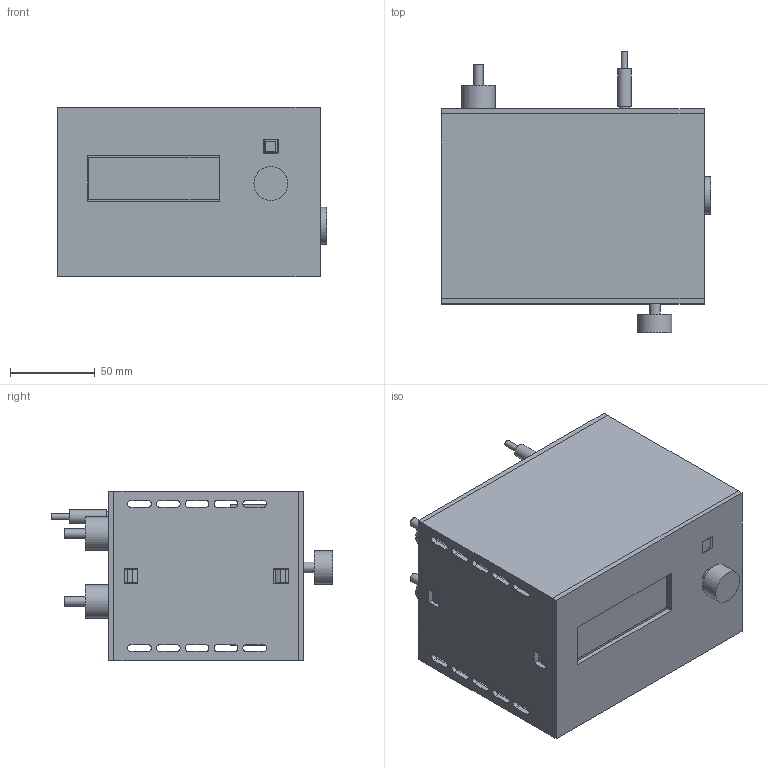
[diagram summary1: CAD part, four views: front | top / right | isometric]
STEP (ISO 10303-21) file: header records copied from the file, then geometry measured from it (millimetres).
FILE_DESCRIPTION(('Open CASCADE Model'),'2;1');
FILE_NAME('Open CASCADE Shape Model','2026-11-09T10:21:47',('Author'),( 'Open CASCADE'),'Open CASCADE STEP processor 7.8','Open CASCADE 7.8' ,'Unknown');
FILE_SCHEMA(('AUTOMOTIVE_DESIGN { 1 0 10303 214 1 1 1 1 }'));
Length unit declared in the file: millimetre
Products named in the file (113): Laboratory_controller_fit_study_v10; 01_Pieces_imprimees; 01_Shell_open_front_and_rear; 02_Removable_front_LCD_A; 03_B_removable_carrier; 04_Rear_panel_with_latches; 05_Translucent_optical_insert; 06_BH1750_removable_carrier; 02_Carte_A_reference; PCB_A; A_C1_ENVELOPE; A_C2_ENVELOPE; A_C3_ENVELOPE; A_D1_ENVELOPE; A_D2_ENVELOPE; A_J1_ENVELOPE; A_J2_ENVELOPE; A_J3_ENVELOPE; A_J4_ENVELOPE; A_J5_ENVELOPE; A_J6_ENVELOPE; A_J7_ENVELOPE; A_JP1_ENVELOPE; A_R1_ENVELOPE; A_R2_ENVELOPE; A_R3_ENVELOPE; A_R4_ENVELOPE; A_R5_ENVELOPE; A_R6_ENVELOPE; A_R7_ENVELOPE; A_U2_ENVELOPE; A_DEVKIT_SOCKET_1; A_DEVKIT_MALE_HEADER_SPACER_1; A_DEVKIT_SOCKET_2; A_DEVKIT_MALE_HEADER_SPACER_2; A_DEVKIT_PCB_REFERENCE_54x27; A_DEVKIT_RF_SHIELD_ENVELOPE; A_DEVKIT_USB_BRIDGE_ENVELOPE; A_DEVKIT_USB_C_ENVELOPE; 03_Carte_B_reference ...
Assembly tree (112 placements, depth 3):
  Laboratory_controller_fit_study_v10
    01_Pieces_imprimees
      01_Shell_open_front_and_rear
      02_Removable_front_LCD_A
      03_B_removable_carrier
      04_Rear_panel_with_latches
      05_Translucent_optical_insert
      06_BH1750_removable_carrier
    02_Carte_A_reference
      PCB_A
      A_C1_ENVELOPE
      A_C2_ENVELOPE
      A_C3_ENVELOPE
      A_D1_ENVELOPE
      A_D2_ENVELOPE
      A_J1_ENVELOPE
      A_J2_ENVELOPE
      A_J3_ENVELOPE
      A_J4_ENVELOPE
      A_J5_ENVELOPE
      A_J6_ENVELOPE
      A_J7_ENVELOPE
      A_JP1_ENVELOPE
      A_R1_ENVELOPE
      A_R2_ENVELOPE
      A_R3_ENVELOPE
      A_R4_ENVELOPE
      A_R5_ENVELOPE
      A_R6_ENVELOPE
      A_R7_ENVELOPE
      A_U2_ENVELOPE
      A_DEVKIT_SOCKET_1
      A_DEVKIT_MALE_HEADER_SPACER_1
      A_DEVKIT_SOCKET_2
      A_DEVKIT_MALE_HEADER_SPACER_2
      A_DEVKIT_PCB_REFERENCE_54x27
      A_DEVKIT_RF_SHIELD_ENVELOPE
      A_DEVKIT_USB_BRIDGE_ENVELOPE
      A_DEVKIT_USB_C_ENVELOPE
    03_Carte_B_reference
      PCB_B
      B_C1_ENVELOPE
      B_C10_ENVELOPE
      B_C2_ENVELOPE
      B_C3_ENVELOPE
      B_C4_ENVELOPE
      B_C5_ENVELOPE
      B_C6_ENVELOPE
      B_C7_ENVELOPE
      B_C8_ENVELOPE
      B_C9_ENVELOPE
      B_D2_ENVELOPE
      B_D3_ENVELOPE
      B_D4_ENVELOPE
      B_D5_ENVELOPE
      B_D6_ENVELOPE
      B_D7_ENVELOPE
      B_D8_ENVELOPE
      B_D9_ENVELOPE
      B_F1_ENVELOPE
Bounding box: 159 x 166 x 100 mm (x, y, z)
Volume: 418084.1 mm3; surface area: 319560.4 mm2
Topology: 105 solids, 106 shells, 1212 faces, 2852 edges, 1889 vertices
Faces by surface type: plane 1124, cylinder 88
Full cylindrical faces by diameter (mm): 2.2 x12, 3 x3, 3.5 x2, 5.5 x2, 5.6 x1, 6 x2, 6.3 x3, 6.4 x1, 7.2 x1, 8 x2, 8.2 x1, 9 x1, 12 x4, 12.5 x2, 14 x1, 15 x2, 16 x1, 20 x5, 22 x2
Entity records: 73220 total; most frequent: CARTESIAN_POINT 13174, DIRECTION 10270, LINE 7037, VECTOR 7037, ORIENTED_EDGE 5704, PCURVE 5704, DEFINITIONAL_REPRESENTATION 5704, EDGE_CURVE 2852
One B-rep face of a CAD part: STEP entity #1736.
In plain terms, the planar face has unit normal (0, 0, 1).
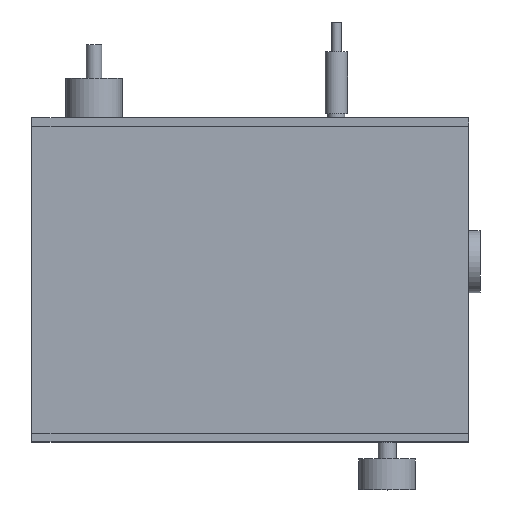
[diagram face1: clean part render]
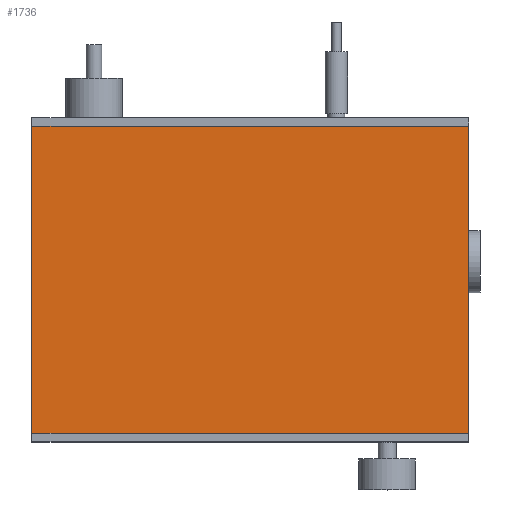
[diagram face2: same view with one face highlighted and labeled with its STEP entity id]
Its self-contained STEP definition (entity closure, numbers rounded to 3 decimals):
#109 = VERTEX_POINT('',#110);
#110 = CARTESIAN_POINT('',(0.,3.,100.));
#117 = PLANE('',#118);
#118 = AXIS2_PLACEMENT_3D('',#119,#120,#121);
#119 = CARTESIAN_POINT('',(0.,3.,0.));
#120 = DIRECTION('',(1.,0.,0.));
#121 = DIRECTION('',(0.,0.,1.));
#129 = PLANE('',#130);
#130 = AXIS2_PLACEMENT_3D('',#131,#132,#133);
#131 = CARTESIAN_POINT('',(0.,3.,0.));
#132 = DIRECTION('',(0.,1.,0.));
#133 = DIRECTION('',(0.,0.,1.));
#170 = VERTEX_POINT('',#171);
#171 = CARTESIAN_POINT('',(0.,112.,100.));
#185 = PLANE('',#186);
#186 = AXIS2_PLACEMENT_3D('',#187,#188,#189);
#187 = CARTESIAN_POINT('',(0.,112.,0.));
#188 = DIRECTION('',(0.,1.,0.));
#189 = DIRECTION('',(0.,0.,1.));
#197 = EDGE_CURVE('',#109,#170,#198,.T.);
#198 = SURFACE_CURVE('',#199,(#203,#210),.PCURVE_S1.);
#199 = LINE('',#200,#201);
#200 = CARTESIAN_POINT('',(0.,3.,100.));
#201 = VECTOR('',#202,1.);
#202 = DIRECTION('',(0.,1.,0.));
#203 = PCURVE('',#117,#204);
#204 = DEFINITIONAL_REPRESENTATION('',(#205),#209);
#205 = LINE('',#206,#207);
#206 = CARTESIAN_POINT('',(100.,0.));
#207 = VECTOR('',#208,1.);
#208 = DIRECTION('',(0.,-1.));
#209 = ( GEOMETRIC_REPRESENTATION_CONTEXT(2) 
PARAMETRIC_REPRESENTATION_CONTEXT() REPRESENTATION_CONTEXT('2D SPACE',''
  ) );
#210 = PCURVE('',#211,#216);
#211 = PLANE('',#212);
#212 = AXIS2_PLACEMENT_3D('',#213,#214,#215);
#213 = CARTESIAN_POINT('',(0.,3.,100.));
#214 = DIRECTION('',(0.,0.,1.));
#215 = DIRECTION('',(1.,0.,0.));
#216 = DEFINITIONAL_REPRESENTATION('',(#217),#221);
#217 = LINE('',#218,#219);
#218 = CARTESIAN_POINT('',(0.,0.));
#219 = VECTOR('',#220,1.);
#220 = DIRECTION('',(0.,1.));
#221 = ( GEOMETRIC_REPRESENTATION_CONTEXT(2) 
PARAMETRIC_REPRESENTATION_CONTEXT() REPRESENTATION_CONTEXT('2D SPACE',''
  ) );
#1582 = EDGE_CURVE('',#109,#1583,#1585,.T.);
#1583 = VERTEX_POINT('',#1584);
#1584 = CARTESIAN_POINT('',(155.,3.,100.));
#1585 = SURFACE_CURVE('',#1586,(#1590,#1597),.PCURVE_S1.);
#1586 = LINE('',#1587,#1588);
#1587 = CARTESIAN_POINT('',(0.,3.,100.));
#1588 = VECTOR('',#1589,1.);
#1589 = DIRECTION('',(1.,0.,0.));
#1590 = PCURVE('',#129,#1591);
#1591 = DEFINITIONAL_REPRESENTATION('',(#1592),#1596);
#1592 = LINE('',#1593,#1594);
#1593 = CARTESIAN_POINT('',(100.,0.));
#1594 = VECTOR('',#1595,1.);
#1595 = DIRECTION('',(0.,1.));
#1596 = ( GEOMETRIC_REPRESENTATION_CONTEXT(2) 
PARAMETRIC_REPRESENTATION_CONTEXT() REPRESENTATION_CONTEXT('2D SPACE',''
  ) );
#1597 = PCURVE('',#211,#1598);
#1598 = DEFINITIONAL_REPRESENTATION('',(#1599),#1603);
#1599 = LINE('',#1600,#1601);
#1600 = CARTESIAN_POINT('',(0.,0.));
#1601 = VECTOR('',#1602,1.);
#1602 = DIRECTION('',(1.,0.));
#1603 = ( GEOMETRIC_REPRESENTATION_CONTEXT(2) 
PARAMETRIC_REPRESENTATION_CONTEXT() REPRESENTATION_CONTEXT('2D SPACE',''
  ) );
#1619 = PLANE('',#1620);
#1620 = AXIS2_PLACEMENT_3D('',#1621,#1622,#1623);
#1621 = CARTESIAN_POINT('',(155.,3.,0.));
#1622 = DIRECTION('',(1.,0.,0.));
#1623 = DIRECTION('',(0.,0.,1.));
#1736 = ADVANCED_FACE('',(#1737),#211,.T.);
#1737 = FACE_BOUND('',#1738,.T.);
#1738 = EDGE_LOOP('',(#1739,#1740,#1741,#1764));
#1739 = ORIENTED_EDGE('',*,*,#197,.F.);
#1740 = ORIENTED_EDGE('',*,*,#1582,.T.);
#1741 = ORIENTED_EDGE('',*,*,#1742,.T.);
#1742 = EDGE_CURVE('',#1583,#1743,#1745,.T.);
#1743 = VERTEX_POINT('',#1744);
#1744 = CARTESIAN_POINT('',(155.,112.,100.));
#1745 = SURFACE_CURVE('',#1746,(#1750,#1757),.PCURVE_S1.);
#1746 = LINE('',#1747,#1748);
#1747 = CARTESIAN_POINT('',(155.,3.,100.));
#1748 = VECTOR('',#1749,1.);
#1749 = DIRECTION('',(0.,1.,0.));
#1750 = PCURVE('',#211,#1751);
#1751 = DEFINITIONAL_REPRESENTATION('',(#1752),#1756);
#1752 = LINE('',#1753,#1754);
#1753 = CARTESIAN_POINT('',(155.,0.));
#1754 = VECTOR('',#1755,1.);
#1755 = DIRECTION('',(0.,1.));
#1756 = ( GEOMETRIC_REPRESENTATION_CONTEXT(2) 
PARAMETRIC_REPRESENTATION_CONTEXT() REPRESENTATION_CONTEXT('2D SPACE',''
  ) );
#1757 = PCURVE('',#1619,#1758);
#1758 = DEFINITIONAL_REPRESENTATION('',(#1759),#1763);
#1759 = LINE('',#1760,#1761);
#1760 = CARTESIAN_POINT('',(100.,0.));
#1761 = VECTOR('',#1762,1.);
#1762 = DIRECTION('',(0.,-1.));
#1763 = ( GEOMETRIC_REPRESENTATION_CONTEXT(2) 
PARAMETRIC_REPRESENTATION_CONTEXT() REPRESENTATION_CONTEXT('2D SPACE',''
  ) );
#1764 = ORIENTED_EDGE('',*,*,#1765,.F.);
#1765 = EDGE_CURVE('',#170,#1743,#1766,.T.);
#1766 = SURFACE_CURVE('',#1767,(#1771,#1778),.PCURVE_S1.);
#1767 = LINE('',#1768,#1769);
#1768 = CARTESIAN_POINT('',(0.,112.,100.));
#1769 = VECTOR('',#1770,1.);
#1770 = DIRECTION('',(1.,0.,0.));
#1771 = PCURVE('',#211,#1772);
#1772 = DEFINITIONAL_REPRESENTATION('',(#1773),#1777);
#1773 = LINE('',#1774,#1775);
#1774 = CARTESIAN_POINT('',(0.,109.));
#1775 = VECTOR('',#1776,1.);
#1776 = DIRECTION('',(1.,0.));
#1777 = ( GEOMETRIC_REPRESENTATION_CONTEXT(2) 
PARAMETRIC_REPRESENTATION_CONTEXT() REPRESENTATION_CONTEXT('2D SPACE',''
  ) );
#1778 = PCURVE('',#185,#1779);
#1779 = DEFINITIONAL_REPRESENTATION('',(#1780),#1784);
#1780 = LINE('',#1781,#1782);
#1781 = CARTESIAN_POINT('',(100.,0.));
#1782 = VECTOR('',#1783,1.);
#1783 = DIRECTION('',(0.,1.));
#1784 = ( GEOMETRIC_REPRESENTATION_CONTEXT(2) 
PARAMETRIC_REPRESENTATION_CONTEXT() REPRESENTATION_CONTEXT('2D SPACE',''
  ) );
